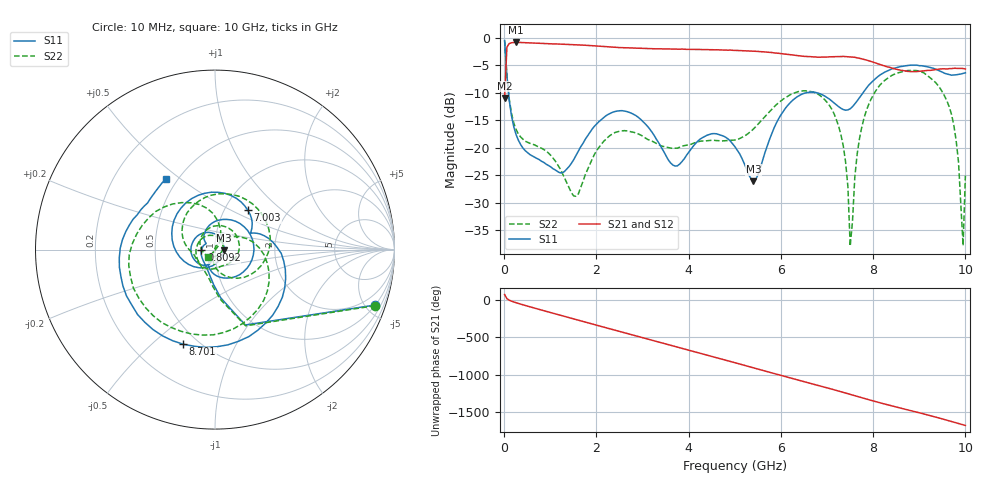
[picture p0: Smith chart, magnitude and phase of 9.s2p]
!Agilent Technologies,N5230C,MY49000813,A.09.42.22
!Agilent N5230C: A.09.42.22
!Date: Friday, August 21, 2026 19:43:58
!Correction: S11(Full 2 Port(1,2))
!S21(Full 2 Port(1,2))
!S12(Full 2 Port(1,2))
!S22(Full 2 Port(1,2))
!S2P File: Measurements: S11, S21, S12, S22:
# Hz S  dB  R 50
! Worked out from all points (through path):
!   201 points, 10 MHz to 10 GHz, reference 50 ohm
!   highest |S21| = -0.86 dB at 259.8 MHz (marker M1); lowest = -10.9 dB at 10 MHz (marker M2)
!   lowest |S11| = -26.1 dB at 5.405 GHz (marker M3), VSWR 1.10, Z = 55.2 - j0.362 ohm
!   |S11| at or under -10 dB: 94.67 MHz to 6.55 GHz (6.455 GHz wide, 194 % of centre); 6.778 GHz to 7.779 GHz (1.001 GHz wide, 13.8 % of centre)
!   |S22| runs from -37.9 to -0.5 dB; largest |S21 - S12| = 0.0068
!   S11 on the Smith chart (normalised r, x): 10 MHz: 1.03, -5.75; 809.2 MHz: 0.86, -0.00; 7.003 GHz: 1.28, +0.61; 8.701 GHz: 0.42, -0.63; 10 GHz: 0.43, +0.44
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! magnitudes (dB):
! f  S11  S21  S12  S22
! 10 MHz  -0.5  -10.9  -10.8  -0.5
! 59.95 MHz  -6.9  -1.7  -1.7  -6.8
! 259.8 MHz  -17.6  -0.9  -0.9  -16.7
! 809.2 MHz  -22.4  -1.0  -1.0  -20.1
! 1.708 GHz  -19.2  -1.3  -1.3  -26.1
! 2.408 GHz  -13.4  -1.7  -1.7  -17.2
! 3.357 GHz  -19.2  -2.0  -2.0  -19.5
! 5.005 GHz  -19.8  -2.3  -2.3  -18.6
! 5.405 GHz  -26.1  -2.4  -2.5  -16.6
! 6.054 GHz  -13.4  -2.9  -2.9  -11.1
! 6.703 GHz  -9.9  -3.5  -3.5  -9.9
! 7.003 GHz  -10.9  -3.5  -3.5  -11.8
! 7.353 GHz  -13.1  -3.4  -3.4  -19.7
! 7.453 GHz  -13.1  -3.4  -3.5  -27.1
! 7.503 GHz  -12.9  -3.5  -3.5  -37.9
! 7.752 GHz  -10.3  -3.8  -3.8  -16.3
! 8.352 GHz  -5.9  -5.4  -5.4  -7.1
! 8.701 GHz  -5.1  -6.0  -6.1  -6.1
! 9.65 GHz  -6.7  -5.6  -5.6  -12.6
! 9.85 GHz  -6.7  -5.6  -5.5  -22.5
! 9.95 GHz  -6.5  -5.6  -5.6  -37.8
! 10 GHz  -6.4  -5.7  -5.7  -25.1
